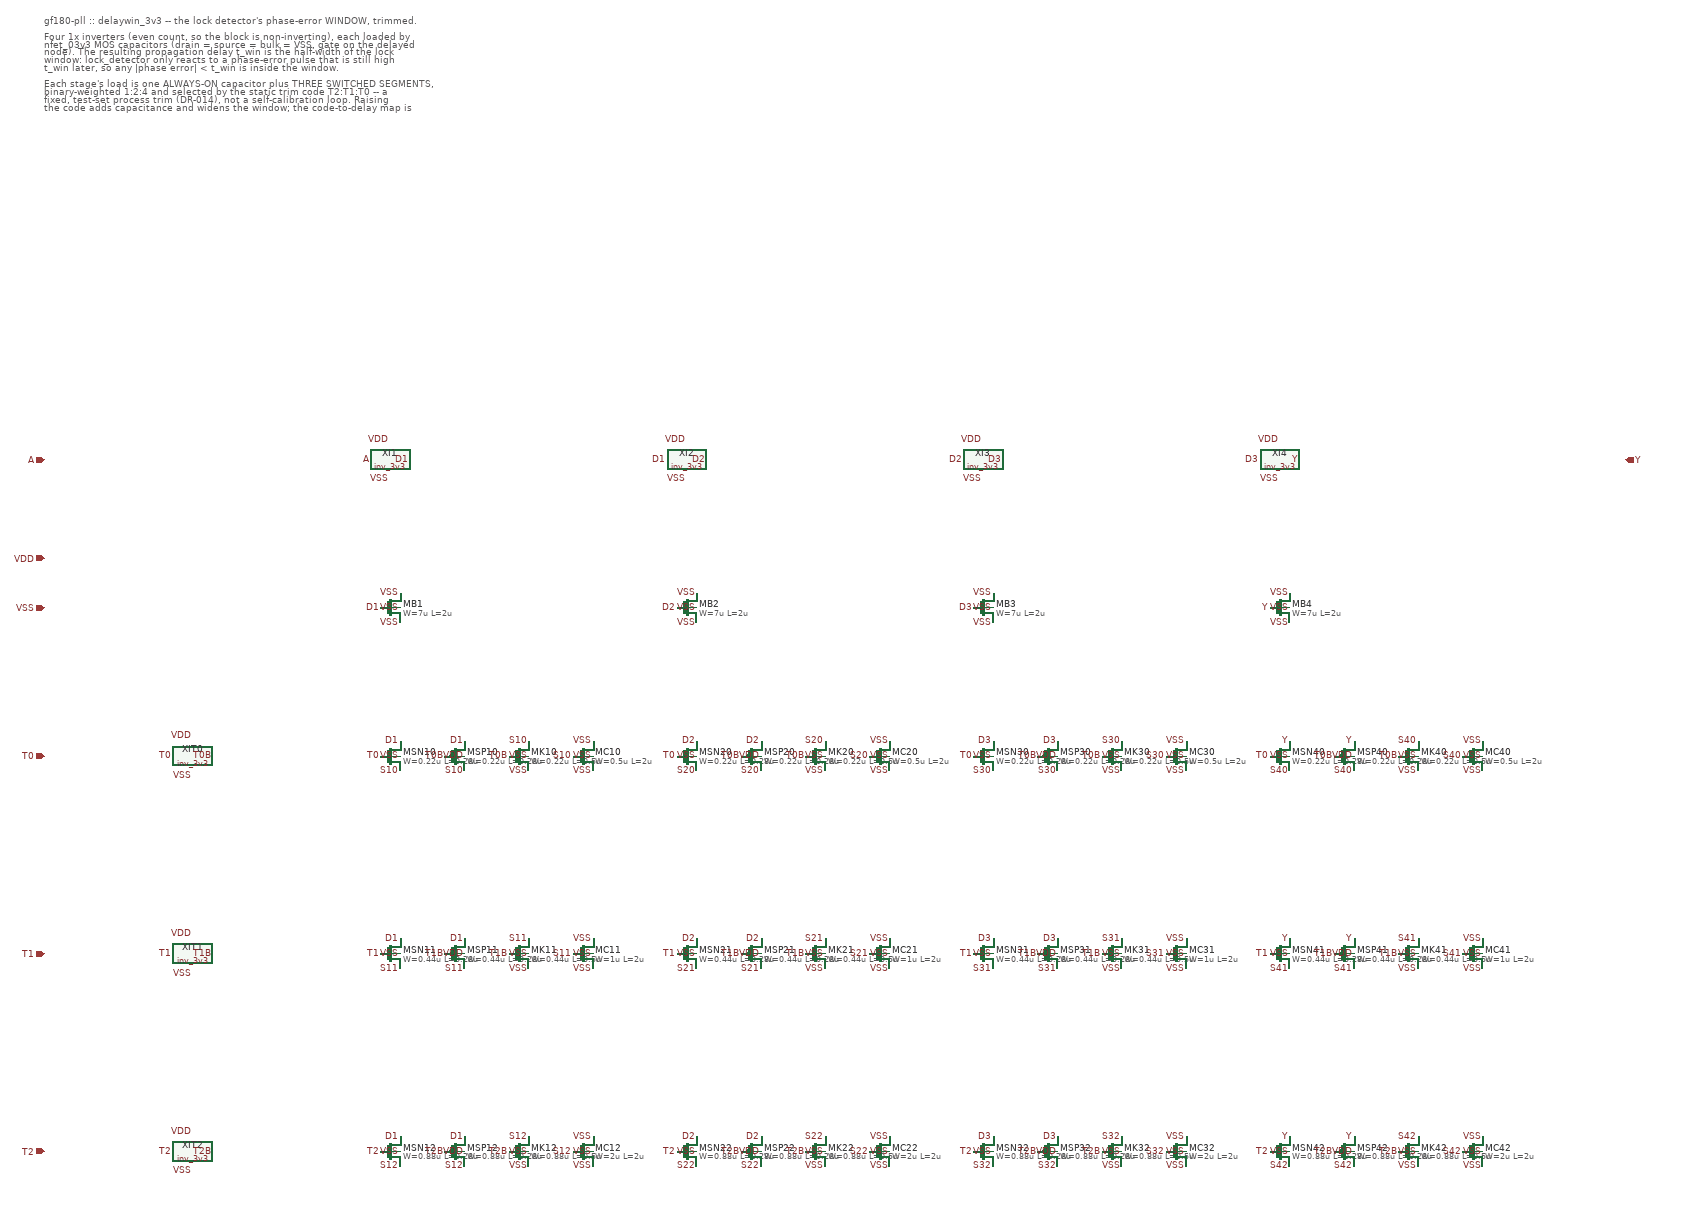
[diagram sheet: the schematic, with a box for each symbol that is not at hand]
v {xschem version=3.4.7 file_version=1.2}
G {}
K {}
V {}
S {}
E {}
T {gf180-pll :: delaywin_3v3 -- the lock detector's phase-error WINDOW, trimmed.

Four 1x inverters (even count, so the block is non-inverting), each loaded by
nfet_03v3 MOS capacitors (drain = source = bulk = VSS, gate on the delayed
node). The resulting propagation delay t_win is the half-width of the lock
window: lock_detector only reacts to a phase-error pulse that is still high
t_win later, so any |phase error| < t_win is inside the window.

Each stage's load is one ALWAYS-ON capacitor plus THREE SWITCHED SEGMENTS,
binary-weighted 1:2:4 and selected by the static trim code T2:T1:T0 -- a
fixed, test-set process trim (DR-014), not a self-calibration loop. Raising
the code adds capacitance and widens the window; the code-to-delay map is
monotonic at every PVT corner because each segment's pass gate and kill
device are scaled by the SAME weight as the segment capacitor they switch, so
the switch's own parasitic scales with the segment rather than adding a
fixed, weight-independent step (an unweighted switch makes code 3 slower than
code 4 -- measured, not assumed).

Segment j is connected to the delayed node by a full transmission gate (Tj
high) and clamped to VSS by a kill device (Tj low), so a deselected segment
is a defined LOW node rather than a floating one.

The load is a MOS capacitor built from the SAME nfet_03v3 primitive as the
logic, not a MIM or poly device -- deliberately, so the window's PVT spread
rides entirely on the MOS corner axis that the default grid already sweeps,
with no independent passive corner axis to leave silently at typical
(sim/README.md "Default corner matrix"). t_win therefore tracks gate delay
over PVT rather than moving against it.

This file is GENERATED by design/gen_delaywin.py -- edit the sizing table
there, not the 60 device placements here.} -700 -900 0 0 0.4 0.4 {}
C {ipin.sym} -700 0 0 0 {name=p1 lab=A}
C {opin.sym} 2500 0 0 0 {name=p2 lab=Y}
C {iopin.sym} -700 200 0 0 {name=p3 lab=VDD}
C {iopin.sym} -700 300 0 0 {name=p4 lab=VSS}
C {ipin.sym} -700 600 0 0 {name=p5 lab=T0}
C {ipin.sym} -700 1000 0 0 {name=p6 lab=T1}
C {ipin.sym} -700 1400 0 0 {name=p7 lab=T2}
C {inv_3v3.sym} -400 600 0 0 {name=XIT0}
C {lab_pin.sym} -440 600 0 0 {name=lt0a lab=T0}
C {lab_pin.sym} -360 600 0 0 {name=lt0b lab=T0B}
C {lab_pin.sym} -400 560 0 0 {name=lt0c lab=VDD}
C {lab_pin.sym} -400 640 0 0 {name=lt0d lab=VSS}
C {inv_3v3.sym} -400 1000 0 0 {name=XIT1}
C {lab_pin.sym} -440 1000 0 0 {name=lt1a lab=T1}
C {lab_pin.sym} -360 1000 0 0 {name=lt1b lab=T1B}
C {lab_pin.sym} -400 960 0 0 {name=lt1c lab=VDD}
C {lab_pin.sym} -400 1040 0 0 {name=lt1d lab=VSS}
C {inv_3v3.sym} -400 1400 0 0 {name=XIT2}
C {lab_pin.sym} -440 1400 0 0 {name=lt2a lab=T2}
C {lab_pin.sym} -360 1400 0 0 {name=lt2b lab=T2B}
C {lab_pin.sym} -400 1360 0 0 {name=lt2c lab=VDD}
C {lab_pin.sym} -400 1440 0 0 {name=lt2d lab=VSS}
C {inv_3v3.sym} 0 0 0 0 {name=XI1}
C {lab_pin.sym} -40 0 0 0 {name=la1 lab=A}
C {lab_pin.sym} 40 0 0 0 {name=la2 lab=D1}
C {lab_pin.sym} 0 -40 0 0 {name=la3 lab=VDD}
C {lab_pin.sym} 0 40 0 0 {name=la4 lab=VSS}
C {nfet_03v3.sym} 0 300 0 0 {name=MB1 model=nfet_03v3 W=7u L=2u nf=1 m=1}
C {lab_pin.sym} -20 300 0 0 {name=lab1 lab=D1}
C {lab_pin.sym} 20 270 0 0 {name=lab2 lab=VSS}
C {lab_pin.sym} 20 330 0 0 {name=lab3 lab=VSS}
C {lab_pin.sym} 20 300 0 0 {name=lab4 lab=VSS}
C {nfet_03v3.sym} 0 600 0 0 {name=MSN10 model=nfet_03v3 W=0.22u L=0.28u nf=1 m=1}
C {lab_pin.sym} -20 600 0 0 {name=la0n1 lab=T0}
C {lab_pin.sym} 20 570 0 0 {name=la0n2 lab=D1}
C {lab_pin.sym} 20 630 0 0 {name=la0n3 lab=S10}
C {lab_pin.sym} 20 600 0 0 {name=la0n4 lab=VSS}
C {pfet_03v3.sym} 130 600 0 0 {name=MSP10 model=pfet_03v3 W=0.22u L=0.28u nf=1 m=1}
C {lab_pin.sym} 110 600 0 0 {name=la0p1 lab=T0B}
C {lab_pin.sym} 150 630 0 0 {name=la0p2 lab=S10}
C {lab_pin.sym} 150 570 0 0 {name=la0p3 lab=D1}
C {lab_pin.sym} 150 600 0 0 {name=la0p4 lab=VDD}
C {nfet_03v3.sym} 260 600 0 0 {name=MK10 model=nfet_03v3 W=0.22u L=0.5u nf=1 m=1}
C {lab_pin.sym} 240 600 0 0 {name=la0k1 lab=T0B}
C {lab_pin.sym} 280 570 0 0 {name=la0k2 lab=S10}
C {lab_pin.sym} 280 630 0 0 {name=la0k3 lab=VSS}
C {lab_pin.sym} 280 600 0 0 {name=la0k4 lab=VSS}
C {nfet_03v3.sym} 390 600 0 0 {name=MC10 model=nfet_03v3 W=0.5u L=2u nf=1 m=1}
C {lab_pin.sym} 370 600 0 0 {name=la0c1 lab=S10}
C {lab_pin.sym} 410 570 0 0 {name=la0c2 lab=VSS}
C {lab_pin.sym} 410 630 0 0 {name=la0c3 lab=VSS}
C {lab_pin.sym} 410 600 0 0 {name=la0c4 lab=VSS}
C {nfet_03v3.sym} 0 1000 0 0 {name=MSN11 model=nfet_03v3 W=0.44u L=0.28u nf=1 m=1}
C {lab_pin.sym} -20 1000 0 0 {name=la1n1 lab=T1}
C {lab_pin.sym} 20 970 0 0 {name=la1n2 lab=D1}
C {lab_pin.sym} 20 1030 0 0 {name=la1n3 lab=S11}
C {lab_pin.sym} 20 1000 0 0 {name=la1n4 lab=VSS}
C {pfet_03v3.sym} 130 1000 0 0 {name=MSP11 model=pfet_03v3 W=0.44u L=0.28u nf=1 m=1}
C {lab_pin.sym} 110 1000 0 0 {name=la1p1 lab=T1B}
C {lab_pin.sym} 150 1030 0 0 {name=la1p2 lab=S11}
C {lab_pin.sym} 150 970 0 0 {name=la1p3 lab=D1}
C {lab_pin.sym} 150 1000 0 0 {name=la1p4 lab=VDD}
C {nfet_03v3.sym} 260 1000 0 0 {name=MK11 model=nfet_03v3 W=0.44u L=0.5u nf=1 m=1}
C {lab_pin.sym} 240 1000 0 0 {name=la1k1 lab=T1B}
C {lab_pin.sym} 280 970 0 0 {name=la1k2 lab=S11}
C {lab_pin.sym} 280 1030 0 0 {name=la1k3 lab=VSS}
C {lab_pin.sym} 280 1000 0 0 {name=la1k4 lab=VSS}
C {nfet_03v3.sym} 390 1000 0 0 {name=MC11 model=nfet_03v3 W=1u L=2u nf=1 m=1}
C {lab_pin.sym} 370 1000 0 0 {name=la1c1 lab=S11}
C {lab_pin.sym} 410 970 0 0 {name=la1c2 lab=VSS}
C {lab_pin.sym} 410 1030 0 0 {name=la1c3 lab=VSS}
C {lab_pin.sym} 410 1000 0 0 {name=la1c4 lab=VSS}
C {nfet_03v3.sym} 0 1400 0 0 {name=MSN12 model=nfet_03v3 W=0.88u L=0.28u nf=1 m=1}
C {lab_pin.sym} -20 1400 0 0 {name=la2n1 lab=T2}
C {lab_pin.sym} 20 1370 0 0 {name=la2n2 lab=D1}
C {lab_pin.sym} 20 1430 0 0 {name=la2n3 lab=S12}
C {lab_pin.sym} 20 1400 0 0 {name=la2n4 lab=VSS}
C {pfet_03v3.sym} 130 1400 0 0 {name=MSP12 model=pfet_03v3 W=0.88u L=0.28u nf=1 m=1}
C {lab_pin.sym} 110 1400 0 0 {name=la2p1 lab=T2B}
C {lab_pin.sym} 150 1430 0 0 {name=la2p2 lab=S12}
C {lab_pin.sym} 150 1370 0 0 {name=la2p3 lab=D1}
C {lab_pin.sym} 150 1400 0 0 {name=la2p4 lab=VDD}
C {nfet_03v3.sym} 260 1400 0 0 {name=MK12 model=nfet_03v3 W=0.88u L=0.5u nf=1 m=1}
C {lab_pin.sym} 240 1400 0 0 {name=la2k1 lab=T2B}
C {lab_pin.sym} 280 1370 0 0 {name=la2k2 lab=S12}
C {lab_pin.sym} 280 1430 0 0 {name=la2k3 lab=VSS}
C {lab_pin.sym} 280 1400 0 0 {name=la2k4 lab=VSS}
C {nfet_03v3.sym} 390 1400 0 0 {name=MC12 model=nfet_03v3 W=2u L=2u nf=1 m=1}
C {lab_pin.sym} 370 1400 0 0 {name=la2c1 lab=S12}
C {lab_pin.sym} 410 1370 0 0 {name=la2c2 lab=VSS}
C {lab_pin.sym} 410 1430 0 0 {name=la2c3 lab=VSS}
C {lab_pin.sym} 410 1400 0 0 {name=la2c4 lab=VSS}
C {inv_3v3.sym} 600 0 0 0 {name=XI2}
C {lab_pin.sym} 560 0 0 0 {name=lb1 lab=D1}
C {lab_pin.sym} 640 0 0 0 {name=lb2 lab=D2}
C {lab_pin.sym} 600 -40 0 0 {name=lb3 lab=VDD}
C {lab_pin.sym} 600 40 0 0 {name=lb4 lab=VSS}
C {nfet_03v3.sym} 600 300 0 0 {name=MB2 model=nfet_03v3 W=7u L=2u nf=1 m=1}
C {lab_pin.sym} 580 300 0 0 {name=lbb1 lab=D2}
C {lab_pin.sym} 620 270 0 0 {name=lbb2 lab=VSS}
C {lab_pin.sym} 620 330 0 0 {name=lbb3 lab=VSS}
C {lab_pin.sym} 620 300 0 0 {name=lbb4 lab=VSS}
C {nfet_03v3.sym} 600 600 0 0 {name=MSN20 model=nfet_03v3 W=0.22u L=0.28u nf=1 m=1}
C {lab_pin.sym} 580 600 0 0 {name=lb0n1 lab=T0}
C {lab_pin.sym} 620 570 0 0 {name=lb0n2 lab=D2}
C {lab_pin.sym} 620 630 0 0 {name=lb0n3 lab=S20}
C {lab_pin.sym} 620 600 0 0 {name=lb0n4 lab=VSS}
C {pfet_03v3.sym} 730 600 0 0 {name=MSP20 model=pfet_03v3 W=0.22u L=0.28u nf=1 m=1}
C {lab_pin.sym} 710 600 0 0 {name=lb0p1 lab=T0B}
C {lab_pin.sym} 750 630 0 0 {name=lb0p2 lab=S20}
C {lab_pin.sym} 750 570 0 0 {name=lb0p3 lab=D2}
C {lab_pin.sym} 750 600 0 0 {name=lb0p4 lab=VDD}
C {nfet_03v3.sym} 860 600 0 0 {name=MK20 model=nfet_03v3 W=0.22u L=0.5u nf=1 m=1}
C {lab_pin.sym} 840 600 0 0 {name=lb0k1 lab=T0B}
C {lab_pin.sym} 880 570 0 0 {name=lb0k2 lab=S20}
C {lab_pin.sym} 880 630 0 0 {name=lb0k3 lab=VSS}
C {lab_pin.sym} 880 600 0 0 {name=lb0k4 lab=VSS}
C {nfet_03v3.sym} 990 600 0 0 {name=MC20 model=nfet_03v3 W=0.5u L=2u nf=1 m=1}
C {lab_pin.sym} 970 600 0 0 {name=lb0c1 lab=S20}
C {lab_pin.sym} 1010 570 0 0 {name=lb0c2 lab=VSS}
C {lab_pin.sym} 1010 630 0 0 {name=lb0c3 lab=VSS}
C {lab_pin.sym} 1010 600 0 0 {name=lb0c4 lab=VSS}
C {nfet_03v3.sym} 600 1000 0 0 {name=MSN21 model=nfet_03v3 W=0.44u L=0.28u nf=1 m=1}
C {lab_pin.sym} 580 1000 0 0 {name=lb1n1 lab=T1}
C {lab_pin.sym} 620 970 0 0 {name=lb1n2 lab=D2}
C {lab_pin.sym} 620 1030 0 0 {name=lb1n3 lab=S21}
C {lab_pin.sym} 620 1000 0 0 {name=lb1n4 lab=VSS}
C {pfet_03v3.sym} 730 1000 0 0 {name=MSP21 model=pfet_03v3 W=0.44u L=0.28u nf=1 m=1}
C {lab_pin.sym} 710 1000 0 0 {name=lb1p1 lab=T1B}
C {lab_pin.sym} 750 1030 0 0 {name=lb1p2 lab=S21}
C {lab_pin.sym} 750 970 0 0 {name=lb1p3 lab=D2}
C {lab_pin.sym} 750 1000 0 0 {name=lb1p4 lab=VDD}
C {nfet_03v3.sym} 860 1000 0 0 {name=MK21 model=nfet_03v3 W=0.44u L=0.5u nf=1 m=1}
C {lab_pin.sym} 840 1000 0 0 {name=lb1k1 lab=T1B}
C {lab_pin.sym} 880 970 0 0 {name=lb1k2 lab=S21}
C {lab_pin.sym} 880 1030 0 0 {name=lb1k3 lab=VSS}
C {lab_pin.sym} 880 1000 0 0 {name=lb1k4 lab=VSS}
C {nfet_03v3.sym} 990 1000 0 0 {name=MC21 model=nfet_03v3 W=1u L=2u nf=1 m=1}
C {lab_pin.sym} 970 1000 0 0 {name=lb1c1 lab=S21}
C {lab_pin.sym} 1010 970 0 0 {name=lb1c2 lab=VSS}
C {lab_pin.sym} 1010 1030 0 0 {name=lb1c3 lab=VSS}
C {lab_pin.sym} 1010 1000 0 0 {name=lb1c4 lab=VSS}
C {nfet_03v3.sym} 600 1400 0 0 {name=MSN22 model=nfet_03v3 W=0.88u L=0.28u nf=1 m=1}
C {lab_pin.sym} 580 1400 0 0 {name=lb2n1 lab=T2}
C {lab_pin.sym} 620 1370 0 0 {name=lb2n2 lab=D2}
C {lab_pin.sym} 620 1430 0 0 {name=lb2n3 lab=S22}
C {lab_pin.sym} 620 1400 0 0 {name=lb2n4 lab=VSS}
C {pfet_03v3.sym} 730 1400 0 0 {name=MSP22 model=pfet_03v3 W=0.88u L=0.28u nf=1 m=1}
C {lab_pin.sym} 710 1400 0 0 {name=lb2p1 lab=T2B}
C {lab_pin.sym} 750 1430 0 0 {name=lb2p2 lab=S22}
C {lab_pin.sym} 750 1370 0 0 {name=lb2p3 lab=D2}
C {lab_pin.sym} 750 1400 0 0 {name=lb2p4 lab=VDD}
C {nfet_03v3.sym} 860 1400 0 0 {name=MK22 model=nfet_03v3 W=0.88u L=0.5u nf=1 m=1}
C {lab_pin.sym} 840 1400 0 0 {name=lb2k1 lab=T2B}
C {lab_pin.sym} 880 1370 0 0 {name=lb2k2 lab=S22}
C {lab_pin.sym} 880 1430 0 0 {name=lb2k3 lab=VSS}
C {lab_pin.sym} 880 1400 0 0 {name=lb2k4 lab=VSS}
C {nfet_03v3.sym} 990 1400 0 0 {name=MC22 model=nfet_03v3 W=2u L=2u nf=1 m=1}
C {lab_pin.sym} 970 1400 0 0 {name=lb2c1 lab=S22}
C {lab_pin.sym} 1010 1370 0 0 {name=lb2c2 lab=VSS}
C {lab_pin.sym} 1010 1430 0 0 {name=lb2c3 lab=VSS}
C {lab_pin.sym} 1010 1400 0 0 {name=lb2c4 lab=VSS}
C {inv_3v3.sym} 1200 0 0 0 {name=XI3}
C {lab_pin.sym} 1160 0 0 0 {name=lc1 lab=D2}
C {lab_pin.sym} 1240 0 0 0 {name=lc2 lab=D3}
C {lab_pin.sym} 1200 -40 0 0 {name=lc3 lab=VDD}
C {lab_pin.sym} 1200 40 0 0 {name=lc4 lab=VSS}
C {nfet_03v3.sym} 1200 300 0 0 {name=MB3 model=nfet_03v3 W=7u L=2u nf=1 m=1}
C {lab_pin.sym} 1180 300 0 0 {name=lcb1 lab=D3}
C {lab_pin.sym} 1220 270 0 0 {name=lcb2 lab=VSS}
C {lab_pin.sym} 1220 330 0 0 {name=lcb3 lab=VSS}
C {lab_pin.sym} 1220 300 0 0 {name=lcb4 lab=VSS}
C {nfet_03v3.sym} 1200 600 0 0 {name=MSN30 model=nfet_03v3 W=0.22u L=0.28u nf=1 m=1}
C {lab_pin.sym} 1180 600 0 0 {name=lc0n1 lab=T0}
C {lab_pin.sym} 1220 570 0 0 {name=lc0n2 lab=D3}
C {lab_pin.sym} 1220 630 0 0 {name=lc0n3 lab=S30}
C {lab_pin.sym} 1220 600 0 0 {name=lc0n4 lab=VSS}
C {pfet_03v3.sym} 1330 600 0 0 {name=MSP30 model=pfet_03v3 W=0.22u L=0.28u nf=1 m=1}
C {lab_pin.sym} 1310 600 0 0 {name=lc0p1 lab=T0B}
C {lab_pin.sym} 1350 630 0 0 {name=lc0p2 lab=S30}
C {lab_pin.sym} 1350 570 0 0 {name=lc0p3 lab=D3}
C {lab_pin.sym} 1350 600 0 0 {name=lc0p4 lab=VDD}
C {nfet_03v3.sym} 1460 600 0 0 {name=MK30 model=nfet_03v3 W=0.22u L=0.5u nf=1 m=1}
C {lab_pin.sym} 1440 600 0 0 {name=lc0k1 lab=T0B}
C {lab_pin.sym} 1480 570 0 0 {name=lc0k2 lab=S30}
C {lab_pin.sym} 1480 630 0 0 {name=lc0k3 lab=VSS}
C {lab_pin.sym} 1480 600 0 0 {name=lc0k4 lab=VSS}
C {nfet_03v3.sym} 1590 600 0 0 {name=MC30 model=nfet_03v3 W=0.5u L=2u nf=1 m=1}
C {lab_pin.sym} 1570 600 0 0 {name=lc0c1 lab=S30}
C {lab_pin.sym} 1610 570 0 0 {name=lc0c2 lab=VSS}
C {lab_pin.sym} 1610 630 0 0 {name=lc0c3 lab=VSS}
C {lab_pin.sym} 1610 600 0 0 {name=lc0c4 lab=VSS}
C {nfet_03v3.sym} 1200 1000 0 0 {name=MSN31 model=nfet_03v3 W=0.44u L=0.28u nf=1 m=1}
C {lab_pin.sym} 1180 1000 0 0 {name=lc1n1 lab=T1}
C {lab_pin.sym} 1220 970 0 0 {name=lc1n2 lab=D3}
C {lab_pin.sym} 1220 1030 0 0 {name=lc1n3 lab=S31}
C {lab_pin.sym} 1220 1000 0 0 {name=lc1n4 lab=VSS}
C {pfet_03v3.sym} 1330 1000 0 0 {name=MSP31 model=pfet_03v3 W=0.44u L=0.28u nf=1 m=1}
C {lab_pin.sym} 1310 1000 0 0 {name=lc1p1 lab=T1B}
C {lab_pin.sym} 1350 1030 0 0 {name=lc1p2 lab=S31}
C {lab_pin.sym} 1350 970 0 0 {name=lc1p3 lab=D3}
C {lab_pin.sym} 1350 1000 0 0 {name=lc1p4 lab=VDD}
C {nfet_03v3.sym} 1460 1000 0 0 {name=MK31 model=nfet_03v3 W=0.44u L=0.5u nf=1 m=1}
C {lab_pin.sym} 1440 1000 0 0 {name=lc1k1 lab=T1B}
C {lab_pin.sym} 1480 970 0 0 {name=lc1k2 lab=S31}
C {lab_pin.sym} 1480 1030 0 0 {name=lc1k3 lab=VSS}
C {lab_pin.sym} 1480 1000 0 0 {name=lc1k4 lab=VSS}
C {nfet_03v3.sym} 1590 1000 0 0 {name=MC31 model=nfet_03v3 W=1u L=2u nf=1 m=1}
C {lab_pin.sym} 1570 1000 0 0 {name=lc1c1 lab=S31}
C {lab_pin.sym} 1610 970 0 0 {name=lc1c2 lab=VSS}
C {lab_pin.sym} 1610 1030 0 0 {name=lc1c3 lab=VSS}
C {lab_pin.sym} 1610 1000 0 0 {name=lc1c4 lab=VSS}
C {nfet_03v3.sym} 1200 1400 0 0 {name=MSN32 model=nfet_03v3 W=0.88u L=0.28u nf=1 m=1}
C {lab_pin.sym} 1180 1400 0 0 {name=lc2n1 lab=T2}
C {lab_pin.sym} 1220 1370 0 0 {name=lc2n2 lab=D3}
C {lab_pin.sym} 1220 1430 0 0 {name=lc2n3 lab=S32}
C {lab_pin.sym} 1220 1400 0 0 {name=lc2n4 lab=VSS}
C {pfet_03v3.sym} 1330 1400 0 0 {name=MSP32 model=pfet_03v3 W=0.88u L=0.28u nf=1 m=1}
C {lab_pin.sym} 1310 1400 0 0 {name=lc2p1 lab=T2B}
C {lab_pin.sym} 1350 1430 0 0 {name=lc2p2 lab=S32}
C {lab_pin.sym} 1350 1370 0 0 {name=lc2p3 lab=D3}
C {lab_pin.sym} 1350 1400 0 0 {name=lc2p4 lab=VDD}
C {nfet_03v3.sym} 1460 1400 0 0 {name=MK32 model=nfet_03v3 W=0.88u L=0.5u nf=1 m=1}
C {lab_pin.sym} 1440 1400 0 0 {name=lc2k1 lab=T2B}
C {lab_pin.sym} 1480 1370 0 0 {name=lc2k2 lab=S32}
C {lab_pin.sym} 1480 1430 0 0 {name=lc2k3 lab=VSS}
C {lab_pin.sym} 1480 1400 0 0 {name=lc2k4 lab=VSS}
C {nfet_03v3.sym} 1590 1400 0 0 {name=MC32 model=nfet_03v3 W=2u L=2u nf=1 m=1}
C {lab_pin.sym} 1570 1400 0 0 {name=lc2c1 lab=S32}
C {lab_pin.sym} 1610 1370 0 0 {name=lc2c2 lab=VSS}
C {lab_pin.sym} 1610 1430 0 0 {name=lc2c3 lab=VSS}
C {lab_pin.sym} 1610 1400 0 0 {name=lc2c4 lab=VSS}
C {inv_3v3.sym} 1800 0 0 0 {name=XI4}
C {lab_pin.sym} 1760 0 0 0 {name=ld1 lab=D3}
C {lab_pin.sym} 1840 0 0 0 {name=ld2 lab=Y}
C {lab_pin.sym} 1800 -40 0 0 {name=ld3 lab=VDD}
C {lab_pin.sym} 1800 40 0 0 {name=ld4 lab=VSS}
C {nfet_03v3.sym} 1800 300 0 0 {name=MB4 model=nfet_03v3 W=7u L=2u nf=1 m=1}
C {lab_pin.sym} 1780 300 0 0 {name=ldb1 lab=Y}
C {lab_pin.sym} 1820 270 0 0 {name=ldb2 lab=VSS}
C {lab_pin.sym} 1820 330 0 0 {name=ldb3 lab=VSS}
C {lab_pin.sym} 1820 300 0 0 {name=ldb4 lab=VSS}
C {nfet_03v3.sym} 1800 600 0 0 {name=MSN40 model=nfet_03v3 W=0.22u L=0.28u nf=1 m=1}
C {lab_pin.sym} 1780 600 0 0 {name=ld0n1 lab=T0}
C {lab_pin.sym} 1820 570 0 0 {name=ld0n2 lab=Y}
C {lab_pin.sym} 1820 630 0 0 {name=ld0n3 lab=S40}
C {lab_pin.sym} 1820 600 0 0 {name=ld0n4 lab=VSS}
C {pfet_03v3.sym} 1930 600 0 0 {name=MSP40 model=pfet_03v3 W=0.22u L=0.28u nf=1 m=1}
C {lab_pin.sym} 1910 600 0 0 {name=ld0p1 lab=T0B}
C {lab_pin.sym} 1950 630 0 0 {name=ld0p2 lab=S40}
C {lab_pin.sym} 1950 570 0 0 {name=ld0p3 lab=Y}
C {lab_pin.sym} 1950 600 0 0 {name=ld0p4 lab=VDD}
C {nfet_03v3.sym} 2060 600 0 0 {name=MK40 model=nfet_03v3 W=0.22u L=0.5u nf=1 m=1}
C {lab_pin.sym} 2040 600 0 0 {name=ld0k1 lab=T0B}
C {lab_pin.sym} 2080 570 0 0 {name=ld0k2 lab=S40}
C {lab_pin.sym} 2080 630 0 0 {name=ld0k3 lab=VSS}
C {lab_pin.sym} 2080 600 0 0 {name=ld0k4 lab=VSS}
C {nfet_03v3.sym} 2190 600 0 0 {name=MC40 model=nfet_03v3 W=0.5u L=2u nf=1 m=1}
C {lab_pin.sym} 2170 600 0 0 {name=ld0c1 lab=S40}
C {lab_pin.sym} 2210 570 0 0 {name=ld0c2 lab=VSS}
C {lab_pin.sym} 2210 630 0 0 {name=ld0c3 lab=VSS}
C {lab_pin.sym} 2210 600 0 0 {name=ld0c4 lab=VSS}
C {nfet_03v3.sym} 1800 1000 0 0 {name=MSN41 model=nfet_03v3 W=0.44u L=0.28u nf=1 m=1}
C {lab_pin.sym} 1780 1000 0 0 {name=ld1n1 lab=T1}
C {lab_pin.sym} 1820 970 0 0 {name=ld1n2 lab=Y}
C {lab_pin.sym} 1820 1030 0 0 {name=ld1n3 lab=S41}
C {lab_pin.sym} 1820 1000 0 0 {name=ld1n4 lab=VSS}
C {pfet_03v3.sym} 1930 1000 0 0 {name=MSP41 model=pfet_03v3 W=0.44u L=0.28u nf=1 m=1}
C {lab_pin.sym} 1910 1000 0 0 {name=ld1p1 lab=T1B}
C {lab_pin.sym} 1950 1030 0 0 {name=ld1p2 lab=S41}
C {lab_pin.sym} 1950 970 0 0 {name=ld1p3 lab=Y}
C {lab_pin.sym} 1950 1000 0 0 {name=ld1p4 lab=VDD}
C {nfet_03v3.sym} 2060 1000 0 0 {name=MK41 model=nfet_03v3 W=0.44u L=0.5u nf=1 m=1}
C {lab_pin.sym} 2040 1000 0 0 {name=ld1k1 lab=T1B}
C {lab_pin.sym} 2080 970 0 0 {name=ld1k2 lab=S41}
C {lab_pin.sym} 2080 1030 0 0 {name=ld1k3 lab=VSS}
C {lab_pin.sym} 2080 1000 0 0 {name=ld1k4 lab=VSS}
C {nfet_03v3.sym} 2190 1000 0 0 {name=MC41 model=nfet_03v3 W=1u L=2u nf=1 m=1}
C {lab_pin.sym} 2170 1000 0 0 {name=ld1c1 lab=S41}
C {lab_pin.sym} 2210 970 0 0 {name=ld1c2 lab=VSS}
C {lab_pin.sym} 2210 1030 0 0 {name=ld1c3 lab=VSS}
C {lab_pin.sym} 2210 1000 0 0 {name=ld1c4 lab=VSS}
C {nfet_03v3.sym} 1800 1400 0 0 {name=MSN42 model=nfet_03v3 W=0.88u L=0.28u nf=1 m=1}
C {lab_pin.sym} 1780 1400 0 0 {name=ld2n1 lab=T2}
C {lab_pin.sym} 1820 1370 0 0 {name=ld2n2 lab=Y}
C {lab_pin.sym} 1820 1430 0 0 {name=ld2n3 lab=S42}
C {lab_pin.sym} 1820 1400 0 0 {name=ld2n4 lab=VSS}
C {pfet_03v3.sym} 1930 1400 0 0 {name=MSP42 model=pfet_03v3 W=0.88u L=0.28u nf=1 m=1}
C {lab_pin.sym} 1910 1400 0 0 {name=ld2p1 lab=T2B}
C {lab_pin.sym} 1950 1430 0 0 {name=ld2p2 lab=S42}
C {lab_pin.sym} 1950 1370 0 0 {name=ld2p3 lab=Y}
C {lab_pin.sym} 1950 1400 0 0 {name=ld2p4 lab=VDD}
C {nfet_03v3.sym} 2060 1400 0 0 {name=MK42 model=nfet_03v3 W=0.88u L=0.5u nf=1 m=1}
C {lab_pin.sym} 2040 1400 0 0 {name=ld2k1 lab=T2B}
C {lab_pin.sym} 2080 1370 0 0 {name=ld2k2 lab=S42}
C {lab_pin.sym} 2080 1430 0 0 {name=ld2k3 lab=VSS}
C {lab_pin.sym} 2080 1400 0 0 {name=ld2k4 lab=VSS}
C {nfet_03v3.sym} 2190 1400 0 0 {name=MC42 model=nfet_03v3 W=2u L=2u nf=1 m=1}
C {lab_pin.sym} 2170 1400 0 0 {name=ld2c1 lab=S42}
C {lab_pin.sym} 2210 1370 0 0 {name=ld2c2 lab=VSS}
C {lab_pin.sym} 2210 1430 0 0 {name=ld2c3 lab=VSS}
C {lab_pin.sym} 2210 1400 0 0 {name=ld2c4 lab=VSS}
